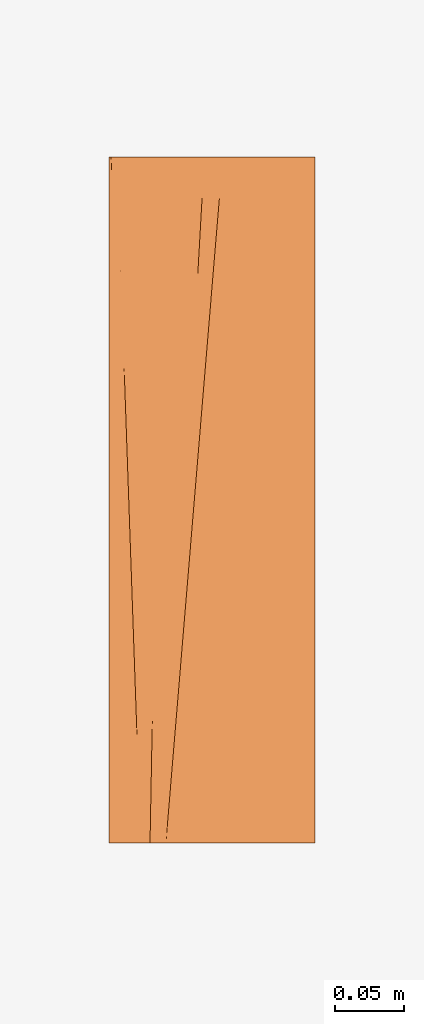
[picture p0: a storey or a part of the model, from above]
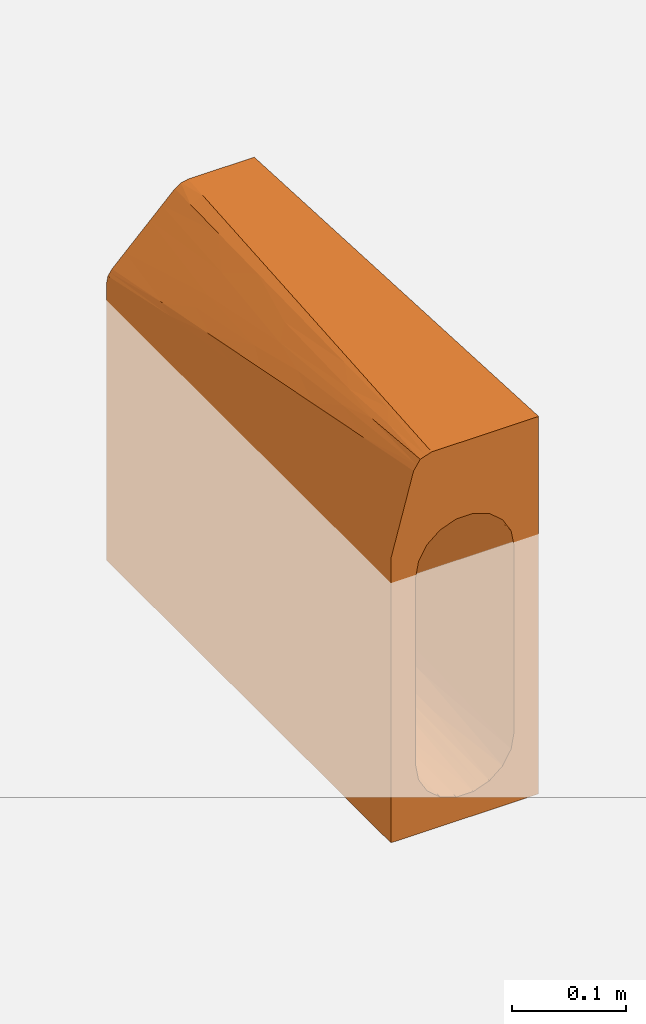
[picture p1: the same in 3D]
Properties of the parts of a building model (IFC2X3)

# File
Description: ViewDefinition [CoordinationView]
File name: 4246 - RH transition kerb - 500mm LG.ifc
Time: 2013-09-02T12:24:06
Written by: Autodesk Revit 2013
Made in: 20120221_2030(x64)

# IfcProject, Project Number
LongName: Project Name; Phase: Project Status

# IfcSite, Default
RefLatitude: 42, 21, 30, 344238; RefLongitude: -71, -3, -35, -194702; RefElevation: 0 mm

# IfcBuilding
Pset_BuildingCommon - NumberOfStoreys: 1
Other - Project Name: Project Name; Project Status: Project Status; Project Issue Date: Issue Date; Project Number: Project Number; Client Name: Owner; Project Address: ## Street City, State Zip

# IfcBuildingStorey, Level 1
LongName: Level 1; Elevation: 0 mm
Constraints - Elevation Base: 0; Elevation: 0 mm
Graphics - Color: 0; Line Weight: 1; Symbol: M_Level Head - Circle: M_Level Head - Circle; Symbol at End 1 Default: no; Line Pattern: Center; Symbol at End 2 Default: yes
Dimensions - Computation Height: 0 mm
Identity Data - Building Story: yes; Name: Level 1; Structural: no

# IfcBuildingElementProxy: 4246 - RH transition kerb - 500mm LG, Civil-Drainage-Channel-ACO-KerbDrain-SP380:4246 - RH transition kerb - 500mm LG:4246 - RH transition kerb - 500mm LG:308659
In: Level 1
Material: ACO Polymer Concrete.
Constraints - Moves With Nearby Elements: no; Level: Level: Level 1
Phasing - Phase Created: New Construction
Dimensions - Volume: 15193178 mm3; Void Width: 150 mm; AccessDepth: 2000 mm; Void Depth: -280 mm; Endcap void: 2000 mm; Access hole: 20 mm; Void Length: 500 mm
Pset_BuildingElementProxyCommon - Reference: 4246 - RH transition kerb - 500mm LG
General - SerialNumber: 0.000000; TagNumber: 0.000000
Data - Product Weight: 31 Kg; Product Standard: BS EN 1433:2002, CE marked, Kitemarked; Channel C.S.A: 0.03mm²; Connection Pipe O.D: N/A; Product Dimensions: 500mm x 150mm x 405/380mm (LxWxH); ACO Hydraulic Design Software: http://www.acodesign.co.uk; Load Class: A 15 - D 400; Drainage Slot Intake area: N/A; Concrete Surround Volume - Load Class A 15 - D 400 - Grass or Asphalt Pavement: N/A; Hydraulic Performance: http://www.aco.co.uk/download.php?id=120; Concrete Surround Volume - Load Class A 15 - D 400 - Concrete Pavement: N/A; Invert Depth: 380/355mm; Drainage Slot Width: N/A; Installation - Concrete Grade: Refer to brochure
Identity Data - Product brochure: http://www.aco.co.uk/download.php?id=120; Type Comments: ACO KerbDrain SP380 splayed RH transition unit 500mm long; Assembly Code: D2040; Fax: +44 (0)1462 815895; Maintenance guidelines: http://www.aco.co.uk/download.php?id=120; Price: POA - contact ACO; Model: ACO KerbDrain SP380; OmniClass Title: Rainwater Removal; Manufacturer: ACO Technologies plc - ACO Water Management Division; Model Description: Combined kerb and drainage system; e-mail Technical: technical@aco.co.uk; Product Page URL: http://www.aco.co.uk/product_detail.php?id=3; Cost: 0; OmniClass Number: 23.70.50.24; Address: ACO Business Park, Hitchin Road, Shefford, Bedfordshire, United Kingdom SG17 5TE; Assembly Description: Rain Water Drainage; Installation guidelines: http://www.aco.co.uk/download.php?id=120; URL: www.aco.co.uk; Product Code: 4246; Telephone: +44 (0)1462 816666; e-mail Sales: customersupport@aco.co.uk
Construction - RH inlet/outlet end cap: no; RH drop kerb: no; Centre Stone: no; LH drop kerb: no; Closing end cap: no; Access Unit: no; LH transition unit: no; SP380 - 1000: no; SP380-500: no; LH inlet/outlet end cap: no; RH transition unit: yes
Materials and Finishes - Access Cover/Frame Material: N/A; Channel Colour: Grey; End Cap Colour: N/A; Access Cover/Frame Colour: N/A; Connection Pipe Material: N/A; Connection Pipe Material Colour: N/A; End Cap Material: N/A; Access Cover/Frame Finish: N/A; Channel Material: Vienite® Synthetic Resin Concrete
Green Building Properties - End Cap Recycled Material Content: N/A; Access Cover/Frame Recycled Material Content: N/A; End Cap Recyclable: N/A; Channel Recyclable: Fully recyclable; Channel Recycled Material Content: 20% minimum; Access Cover/Frame Recyclable: N/A
Other - CreatedBy: www.aco.co.uk; Revision: 1

# IfcOpeningElement: Recess (3)
In: Level 1
Constraints - Level: Level: Level 1; Room Bounding: yes; Related to Mass: no; Height Offset From Level: 0 mm
Dimensions - Area: 151470000 mm2; Volume: 60567000000 mm3; Thickness: 400 mm; Perimeter: 51360 mm
Phasing - Phase Created: New Construction
Structural - Structural: no; Enable Analytical Model: no
Graphics - Coarse Scale Fill Color: 0
Construction - Default Thickness: 400 mm; Function: 0
Materials and Finishes - Structural Material: Plant
Analytical Properties - Roughness: 1; Absorptance: 0.1

# IfcSlab: Floor:Generic Floor - 400mm, Floor:Generic Floor - 400mm:193825
In: Level 1
PredefinedType: FLOOR; Material: Plant 400 mm
Constraints - Level: Level: Level 1; Room Bounding: yes; Related to Mass: no; Height Offset From Level: 0 mm
Dimensions - Area: 151470000 mm2; Volume: 60567000000 mm3; Thickness: 400 mm; Perimeter: 51360 mm
Phasing - Phase Created: New Construction
Structural - Structural: no; Enable Analytical Model: no
Pset_SlabCommon - Reference: Generic Floor - 400mm; IsExternal: no; LoadBearing: yes
Graphics - Coarse Scale Fill Color: 0
Construction - Default Thickness: 400 mm; Function: 0
Materials and Finishes - Structural Material: Plant
Analytical Properties - Roughness: 1; Absorptance: 0.1
